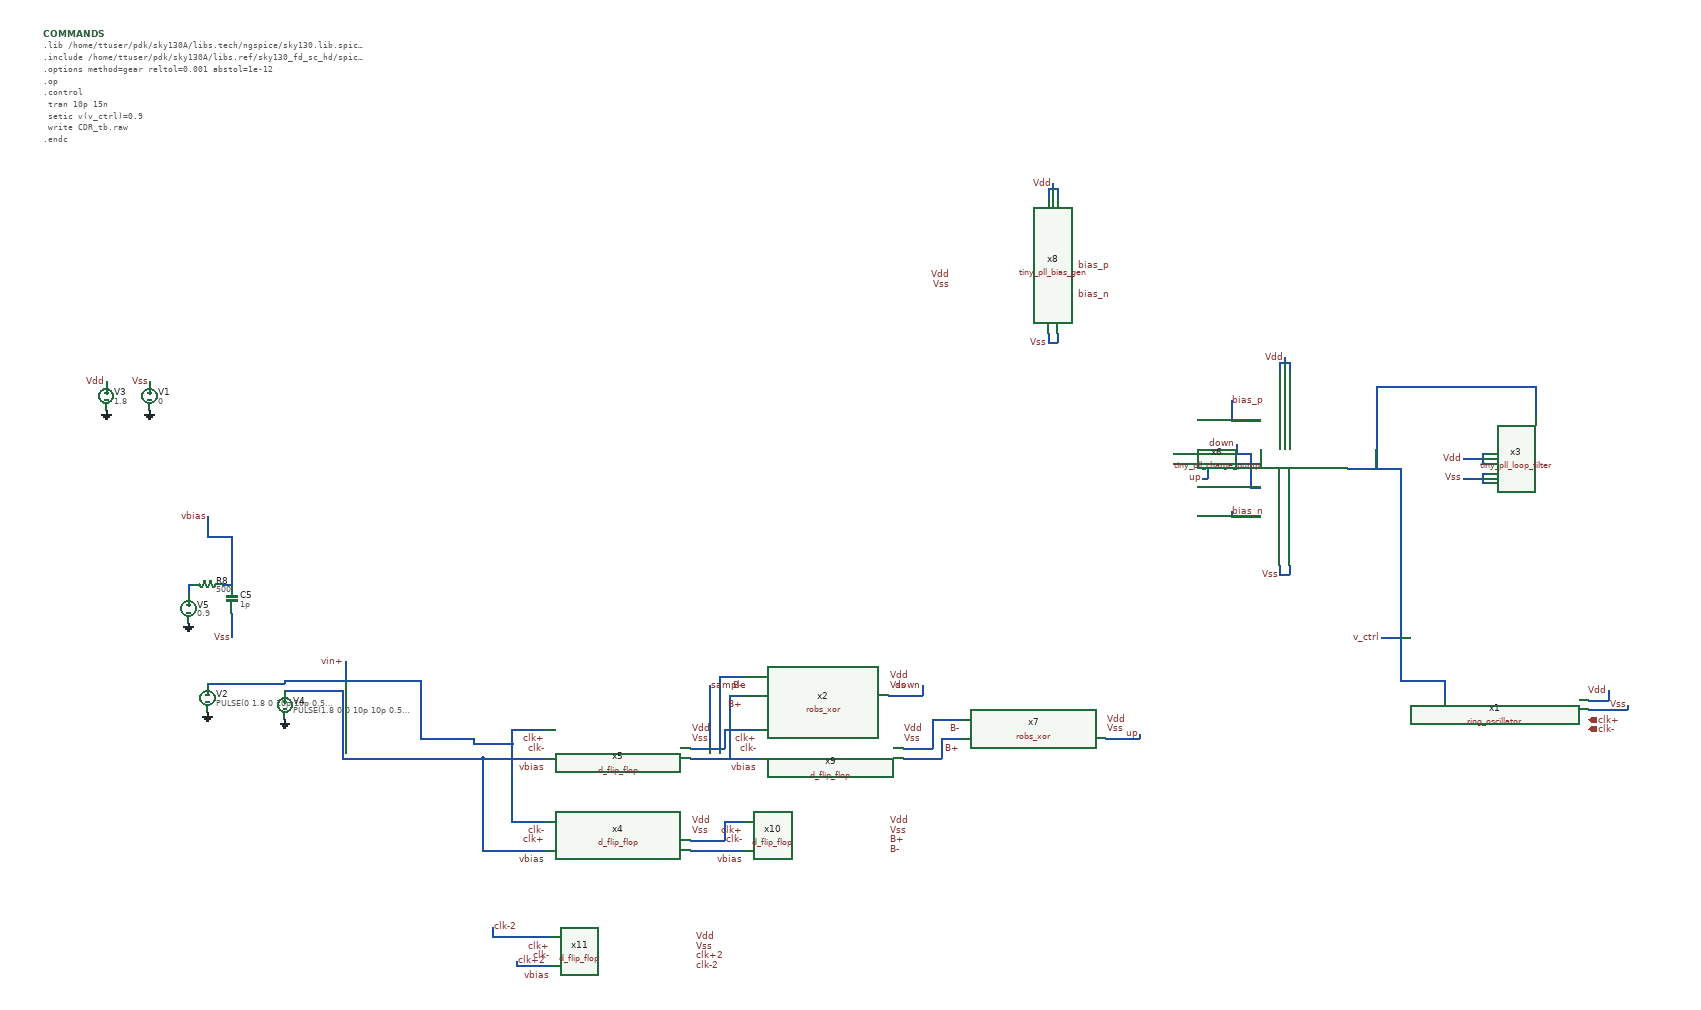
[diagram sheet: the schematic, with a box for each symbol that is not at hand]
v {xschem version=3.4.5 file_version=1.2
}
G {}
K {}
V {}
S {}
E {}
N -1600 470 -1570 470 {
lab=vin+}
N -1600 490 -1570 490 {
lab=#net1}
N -1730 270 -1710 270 {
lab=vbias}
N -1710 330 -1710 380 {
lab=Vss}
N -1710 220 -1710 270 {
lab=vbias}
N -1710 170 -1710 220 {
lab=vbias}
N -1760 170 -1710 170 {
lab=vbias}
N -1760 130 -1760 170 {
lab=vbias}
N -1800 270 -1790 270 {
lab=#net2}
N -1800 270 -1800 290 {
lab=#net2}
N -1570 490 -1530 490 {
lab=#net1}
N -1570 470 -1490 470 {
lab=vin+}
N -1530 490 -1490 490 {
lab=#net1}
N 710 470 800 470 {
lab=v_ctrl}
N 800 470 800 510 {
lab=v_ctrl}
N 710 30 710 470 {
lab=v_ctrl}
N 460 -190 460 -170 {
lab=Vdd}
N 460 -190 480 -190 {
lab=Vdd}
N 480 -190 480 -170 {
lab=Vdd}
N 470 -200 470 -190 {
lab=Vdd}
N 460 230 460 250 {
lab=Vss}
N 460 250 480 250 {
lab=Vss}
N 480 230 480 250 {
lab=Vss}
N 600 30 710 30 {
lab=v_ctrl}
N -20 -550 -20 -530 {
lab=Vdd}
N -20 -550 0 -550 {
lab=Vdd}
N 0 -550 0 -530 {
lab=Vdd}
N -10 -560 -10 -550 {
lab=Vdd}
N -20 -250 -20 -230 {
lab=Vss}
N -20 -230 0 -230 {
lab=Vss}
N 0 -250 0 -230 {
lab=Vss}
N 240 0 360 0 {
lab=down}
N 880 0 890 0 {
lab=Vdd}
N 880 0 880 20 {
lab=Vdd}
N 880 20 890 20 {
lab=Vdd}
N 840 10 880 10 {
lab=Vdd}
N 880 40 890 40 {
lab=Vss}
N 880 40 880 60 {
lab=Vss}
N 880 60 890 60 {
lab=Vss}
N 840 50 880 50 {
lab=Vss}
N 990 -140 990 -80 {
lab=v_ctrl}
N 660 -140 990 -140 {
lab=v_ctrl}
N 660 -140 660 30 {
lab=v_ctrl}
N -1480 630 -1210 630 {
lab=#net1}
N -1480 490 -1480 630 {
lab=#net1}
N -1490 490 -1480 490 {
lab=#net1}
N 360 -0 370 -0 {
lab=down}
N 370 -20 370 -0 {
lab=down}
N 310 20 310 50 {
lab=up}
N 300 50 310 50 {
lab=up}
N 670 380 710 380 {
lab=v_ctrl}
N 420 -10 420 0 {
lab=up}
N 240 20 310 20 {
lab=up}
N 310 20 360 20 {
lab=up}
N 1100 510 1140 510 {
lab=Vdd}
N 1140 490 1140 510 {
lab=Vdd}
N 1100 530 1180 530 {
lab=Vss}
N 1180 520 1180 530 {
lab=Vss}
N -1320 590 -1210 590 {
lab=vin+}
N -1320 470 -1320 590 {
lab=vin+}
N -1490 470 -1320 470 {
lab=vin+}
N -1760 475 -1600 475 {
lab=vin+}
N -1600 470 -1600 475 {
lab=vin+}
N -1475 430 -1475 470 {
lab=vin+}
N 360 -110 360 -70 {
lab=bias_p}
N 360 -70 420 -70 {
lab=bias_p}
N 360 120 360 130 {
lab=bias_n}
N 360 130 420 130 {
lab=bias_n}
N 370 -0 400 -0 {
lab=down}
N 400 -0 400 70 {
lab=down}
N 400 70 420 70 {
lab=down}
N 360 20 420 20 {
lab=up}
N 420 0 420 20 {
lab=up}
N -1210 600 -1130 600 {
lab=vin+}
N -1130 570 -1130 600 {
lab=vin+}
N -1130 570 -1060 570 {
lab=vin+}
N -1130 600 -1130 750 {
lab=vin+}
N -1130 750 -1130 760 {
lab=vin+}
N -1130 760 -1060 760 {
lab=vin+}
N -1190 630 -1190 780 {
lab=#net1}
N -1210 630 -1190 630 {
lab=#net1}
N -1190 630 -1100 630 {
lab=#net1}
N -700 460 -700 610 {
lab=sample}
N -700 460 -650 460 {
lab=sample}
N -680 500 -650 500 {
lab=#net3}
N -680 500 -680 630 {
lab=#net3}
N -1100 630 -1060 630 {
lab=#net1}
N -1190 820 -1060 820 {
lab=#net1}
N -1190 780 -1190 820 {
lab=#net1}
N -760 800 -690 800 {
lab=#net4}
N -690 760 -690 800 {
lab=#net4}
N -690 760 -650 760 {
lab=#net4}
N -760 820 -650 820 {
lab=#net5}
N -690 630 -620 630 {
lab=#net3}
N -320 610 -260 610 {
lab=#net6}
N -260 550 -260 610 {
lab=#net6}
N -260 550 -200 550 {
lab=#net6}
N -240 590 -200 590 {
lab=#net7}
N -240 590 -240 630 {
lab=#net7}
N -320 630 -240 630 {
lab=#net7}
N -760 630 -690 630 {
lab=#net3}
N -760 610 -690 610 {
lab=sample}
N -690 570 -690 610 {
lab=sample}
N -690 570 -620 570 {
lab=sample}
N -350 500 -280 500 {
lab=down}
N -280 480 -280 500 {
lab=down}
N 100 590 170 590 {
lab=up}
N 170 580 170 590 {
lab=up}
N -1210 590 -1210 600 {
lab=vin+}
N -720 480 -720 610 {
lab=sample}
N -1170 1000 -1050 1000 {
lab=clk-2}
N -1170 980 -1170 1000 {
lab=clk-2}
N -1120 1050 -1120 1060 {
lab=clk+2}
N -1120 1060 -1050 1060 {
lab=clk+2}
C {devices/vsource.sym} -1970 -120 0 0 {name=V3 value=1.8 savecurrent=false}
C {devices/gnd.sym} -1970 -90 0 0 {name=l3 lab=GND}
C {devices/lab_wire.sym} -1970 -150 0 0 {name=p5 sig_type=std_logic lab=Vdd
}
C {devices/vsource.sym} -1880 -120 0 0 {name=V1 value=0 savecurrent=false}
C {devices/gnd.sym} -1880 -90 0 0 {name=l1 lab=GND}
C {devices/lab_wire.sym} -1880 -150 0 0 {name=p1 sig_type=std_logic lab=Vss
}
C {devices/simulator_commands_shown.sym} -2100 -870 0 0 {name=COMMANDS
simulator=ngspice
only_toplevel=false 
value="
.lib /home/ttuser/pdk/sky130A/libs.tech/ngspice/sky130.lib.spice tt
.include /home/ttuser/pdk/sky130A/libs.ref/sky130_fd_sc_hd/spice/sky130_fd_sc_hd.spice
.options method=gear reltol=0.001 abstol=1e-12
.op
.control
  tran 10p 15n
  setic v(v_ctrl)=0.9
  write CDR_tb.raw
.endc
"}
C {devices/vsource.sym} -1760 505 0 0 {name=V2 value="PULSE(0 1.8 0 10p 10p 0.5n 1n)" savecurrent=false
lab=vin+}
C {devices/gnd.sym} -1760 535 0 0 {name=l2 lab=GND}
C {devices/vsource.sym} -1600 520 0 0 {name=V4 value="PULSE(1.8 0 0 10p 10p 0.5n 1n)" savecurrent=false}
C {devices/gnd.sym} -1600 550 0 0 {name=l4 lab=GND}
C {devices/vsource.sym} -1800 320 0 0 {name=V5 value=0.9 savecurrent=false}
C {devices/gnd.sym} -1800 350 0 0 {name=l5 lab=GND
value=vbias}
C {devices/lab_wire.sym} -1760 130 0 0 {name=p28 sig_type=std_logic lab=vbias
}
C {devices/res.sym} -1760 270 1 0 {name=R8
value=500
footprint=1206
device=resistor
m=1}
C {devices/capa.sym} -1710 300 0 0 {name=C5
m=1
value=1p
footprint=1206
device="ceramic capacitor"}
C {devices/lab_wire.sym} -1710 380 0 0 {name=p29 sig_type=std_logic lab=Vss
}
C {tiny_pll_charge_pump.sym} 520 30 0 0 {name=x6}
C {devices/lab_wire.sym} 470 -200 0 0 {name=p14 sig_type=std_logic lab=Vdd
}
C {devices/lab_wire.sym} 460 250 0 0 {name=p35 sig_type=std_logic lab=Vss
}
C {tiny_pll_bias_gen.sym} -100 -370 0 0 {name=x8}
C {devices/lab_wire.sym} -10 -560 0 0 {name=p43 sig_type=std_logic lab=Vdd
}
C {devices/lab_wire.sym} -20 -230 0 0 {name=p44 sig_type=std_logic lab=Vss
}
C {devices/lab_wire.sym} 40 -390 0 1 {name=p47 sig_type=std_logic lab=bias_p
}
C {devices/lab_wire.sym} 40 -330 0 1 {name=p48 sig_type=std_logic lab=bias_n
}
C {devices/opin.sym} 1100 570 0 0 {name=p17 lab=clk-}
C {tiny_pll_loop_filter.sym} 990 40 0 0 {name=x3}
C {devices/lab_wire.sym} 840 10 0 0 {name=p30 sig_type=std_logic lab=Vdd
}
C {devices/lab_wire.sym} 840 50 0 0 {name=p31 sig_type=std_logic lab=Vss
}
C {devices/opin.sym} 1100 550 0 0 {name=p32 lab=clk+}
C {devices/lab_wire.sym} -220 -370 0 0 {name=p45 sig_type=std_logic lab=Vdd
}
C {devices/lab_wire.sym} -220 -350 0 0 {name=p46 sig_type=std_logic lab=Vss
}
C {devices/lab_wire.sym} 370 -20 0 0 {name=p7 sig_type=std_logic lab=down
}
C {devices/lab_wire.sym} 300 50 0 0 {name=p26 sig_type=std_logic lab=up
}
C {devices/lab_wire.sym} 670 380 0 0 {name=p56 sig_type=std_logic lab=v_ctrl
}
C {devices/lab_wire.sym} 1140 490 0 0 {name=p38 sig_type=std_logic lab=Vdd
}
C {devices/lab_wire.sym} 1180 520 0 0 {name=p39 sig_type=std_logic lab=Vss
}
C {devices/lab_wire.sym} -1475 430 0 0 {name=p9 sig_type=std_logic lab=vin+
}
C {devices/lab_wire.sym} 360 -110 0 1 {name=p10 sig_type=std_logic lab=bias_p
}
C {devices/lab_wire.sym} 360 120 0 1 {name=p11 sig_type=std_logic lab=bias_n
}
C {ring_oscillator.sym} 950 540 0 0 {name=x1}
C {devices/lab_wire.sym} -1060 800 0 0 {name=p12 sig_type=std_logic lab=clk+
}
C {devices/lab_wire.sym} -1060 780 0 0 {name=p13 sig_type=std_logic lab=clk-
}
C {devices/lab_wire.sym} -1060 840 0 0 {name=p19 sig_type=std_logic lab=vbias
}
C {devices/lab_wire.sym} -760 570 0 1 {name=p2 sig_type=std_logic lab=Vdd}
C {devices/lab_wire.sym} -760 590 0 1 {name=p4 sig_type=std_logic lab=Vss}
C {devices/lab_wire.sym} -760 760 0 1 {name=p6 sig_type=std_logic lab=Vdd}
C {devices/lab_wire.sym} -760 780 0 1 {name=p8 sig_type=std_logic lab=Vss}
C {devices/lab_wire.sym} -350 760 0 1 {name=p3 sig_type=std_logic lab=Vdd}
C {devices/lab_wire.sym} -350 780 0 1 {name=p15 sig_type=std_logic lab=Vss}
C {devices/lab_wire.sym} -320 570 0 1 {name=p16 sig_type=std_logic lab=Vdd}
C {devices/lab_wire.sym} -620 590 0 0 {name=p18 sig_type=std_logic lab=clk+}
C {devices/lab_wire.sym} -620 610 0 0 {name=p20 sig_type=std_logic lab=clk-}
C {devices/lab_wire.sym} -620 650 0 0 {name=p21 sig_type=std_logic lab=vbias}
C {devices/lab_wire.sym} -650 780 0 0 {name=p22 sig_type=std_logic lab=clk+}
C {devices/lab_wire.sym} -650 800 0 0 {name=p24 sig_type=std_logic lab=clk-}
C {devices/lab_wire.sym} -650 840 0 0 {name=p27 sig_type=std_logic lab=vbias}
C {devices/lab_wire.sym} -350 800 0 1 {name=p36 sig_type=std_logic lab=B+}
C {devices/lab_wire.sym} -350 820 0 1 {name=p37 sig_type=std_logic lab=B-}
C {devices/lab_wire.sym} -650 480 0 0 {name=p42 sig_type=std_logic lab=B-}
C {devices/lab_wire.sym} -650 520 0 0 {name=p49 sig_type=std_logic lab=B+}
C {robs_xor.sym} -500 490 0 0 {name=x2}
C {devices/lab_wire.sym} -200 570 0 0 {name=p51 sig_type=std_logic lab=B-}
C {devices/lab_wire.sym} -200 610 0 0 {name=p52 sig_type=std_logic lab=B+}
C {robs_xor.sym} -50 580 0 0 {name=x7}
C {devices/lab_wire.sym} 100 570 0 1 {name=p53 sig_type=std_logic lab=Vss}
C {devices/lab_wire.sym} 100 550 0 1 {name=p54 sig_type=std_logic lab=Vdd}
C {devices/lab_wire.sym} -350 480 0 1 {name=p55 sig_type=std_logic lab=Vss}
C {devices/lab_wire.sym} -350 460 0 1 {name=p57 sig_type=std_logic lab=Vdd}
C {d_flip_flop.sym} -910 610 0 0 {name=x5}
C {d_flip_flop.sym} -910 800 0 0 {name=x4}
C {d_flip_flop.sym} -470 610 0 0 {name=x9}
C {d_flip_flop.sym} -500 800 0 0 {name=x10}
C {devices/lab_wire.sym} -320 590 0 1 {name=p63 sig_type=std_logic lab=Vss}
C {devices/lab_wire.sym} -280 480 0 0 {name=p41 sig_type=std_logic lab=down
}
C {devices/lab_wire.sym} 170 580 0 0 {name=p50 sig_type=std_logic lab=up
}
C {devices/lab_wire.sym} -1060 590 0 0 {name=p60 sig_type=std_logic lab=clk+}
C {devices/lab_wire.sym} -1060 610 0 0 {name=p61 sig_type=std_logic lab=clk-}
C {devices/lab_wire.sym} -1060 650 0 0 {name=p62 sig_type=std_logic lab=vbias}
C {devices/lab_wire.sym} -720 480 0 1 {name=p23 sig_type=std_logic lab=sample}
C {d_flip_flop.sym} -900 1040 0 0 {name=x11}
C {devices/lab_wire.sym} -1050 1020 0 0 {name=p25 sig_type=std_logic lab=clk+}
C {devices/lab_wire.sym} -1050 1040 0 0 {name=p33 sig_type=std_logic lab=clk-}
C {devices/lab_wire.sym} -750 1040 0 1 {name=p34 sig_type=std_logic lab=clk+2}
C {devices/lab_wire.sym} -750 1060 0 1 {name=p40 sig_type=std_logic lab=clk-2}
C {devices/lab_wire.sym} -750 1000 0 1 {name=p58 sig_type=std_logic lab=Vdd}
C {devices/lab_wire.sym} -750 1020 0 1 {name=p59 sig_type=std_logic lab=Vss}
C {devices/lab_wire.sym} -1120 1050 0 1 {name=p64 sig_type=std_logic lab=clk+2}
C {devices/lab_wire.sym} -1170 980 0 1 {name=p65 sig_type=std_logic lab=clk-2}
C {devices/lab_wire.sym} -1050 1080 0 0 {name=p66 sig_type=std_logic lab=vbias
}
